VERSION 5.7 ;
  NOWIREEXTENSIONATPIN ON ;
  DIVIDERCHAR "/" ;
  BUSBITCHARS "[]" ;
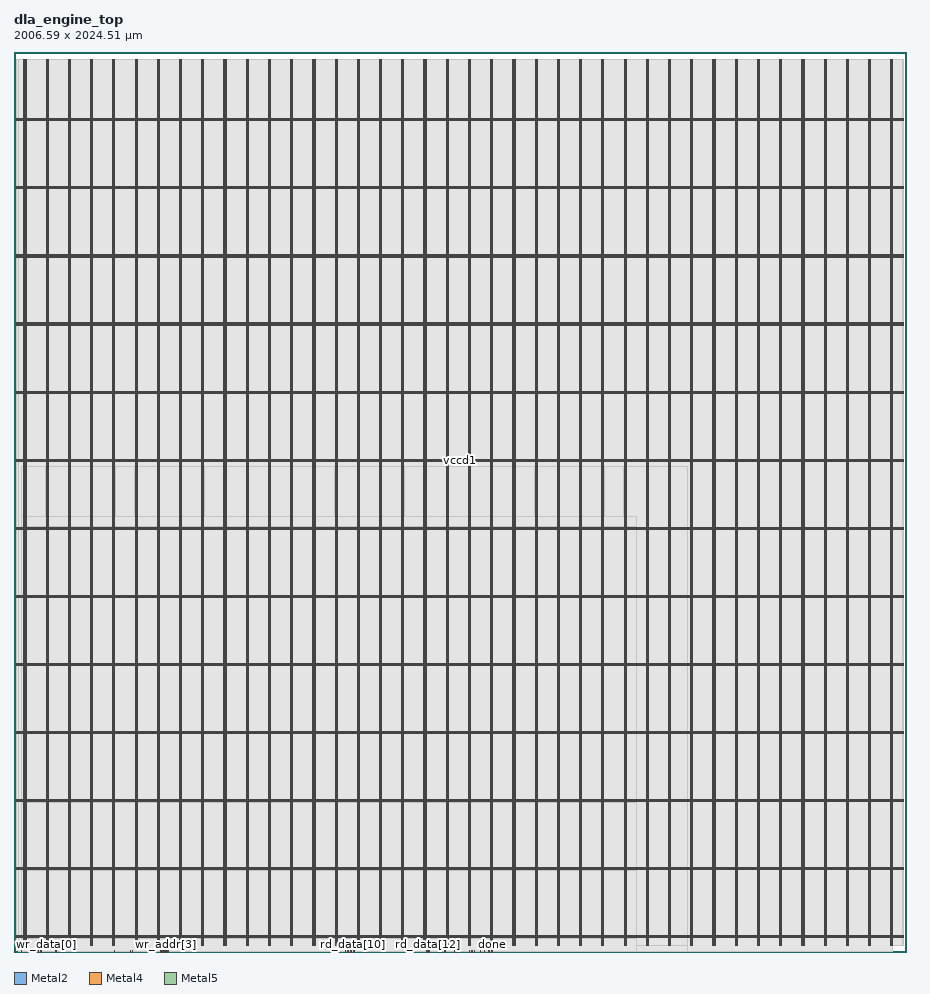
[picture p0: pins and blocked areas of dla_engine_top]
MACRO dla_engine_top
  CLASS BLOCK ;
  FOREIGN dla_engine_top ;
  ORIGIN 0.000 0.000 ;
  SIZE 2006.585 BY 2024.505 ;
  PIN busy
    DIRECTION OUTPUT ;
    USE SIGNAL ;
    ANTENNADIFFAREA 1.986000 ;
    PORT
      LAYER Metal2 ;
        RECT 1048.320 0.000 1048.880 4.000 ;
    END
  END busy
  PIN clk
    DIRECTION INPUT ;
    USE SIGNAL ;
    ANTENNAGATEAREA 4.738000 ;
    ANTENNADIFFAREA 0.820800 ;
    PORT
      LAYER Metal2 ;
        RECT 110.880 0.000 111.440 4.000 ;
    END
  END clk
  PIN done
    DIRECTION OUTPUT ;
    USE SIGNAL ;
    ANTENNADIFFAREA 1.986000 ;
    PORT
      LAYER Metal2 ;
        RECT 1075.200 0.000 1075.760 4.000 ;
    END
  END done
  PIN rd_addr[0]
    DIRECTION INPUT ;
    USE SIGNAL ;
    ANTENNAGATEAREA 0.396000 ;
    PORT
      LAYER Metal2 ;
        RECT 1028.160 0.000 1028.720 4.000 ;
    END
  END rd_addr[0]
  PIN rd_addr[1]
    DIRECTION INPUT ;
    USE SIGNAL ;
    ANTENNAGATEAREA 0.741000 ;
    PORT
      LAYER Metal2 ;
        RECT 1034.880 0.000 1035.440 4.000 ;
    END
  END rd_addr[1]
  PIN rd_addr[2]
    DIRECTION INPUT ;
    USE SIGNAL ;
    ANTENNAGATEAREA 0.396000 ;
    PORT
      LAYER Metal2 ;
        RECT 1024.800 0.000 1025.360 4.000 ;
    END
  END rd_addr[2]
  PIN rd_addr[3]
    DIRECTION INPUT ;
    USE SIGNAL ;
    ANTENNAGATEAREA 0.396000 ;
    PORT
      LAYER Metal2 ;
        RECT 1031.520 0.000 1032.080 4.000 ;
    END
  END rd_addr[3]
  PIN rd_data[0]
    DIRECTION OUTPUT ;
    USE SIGNAL ;
    ANTENNADIFFAREA 1.986000 ;
    PORT
      LAYER Metal2 ;
        RECT 725.760 0.000 726.320 4.000 ;
    END
  END rd_data[0]
  PIN rd_data[10]
    DIRECTION OUTPUT ;
    USE SIGNAL ;
    ANTENNADIFFAREA 1.986000 ;
    PORT
      LAYER Metal2 ;
        RECT 762.720 0.000 763.280 4.000 ;
    END
  END rd_data[10]
  PIN rd_data[11]
    DIRECTION OUTPUT ;
    USE SIGNAL ;
    ANTENNADIFFAREA 1.986000 ;
    PORT
      LAYER Metal2 ;
        RECT 789.600 0.000 790.160 4.000 ;
    END
  END rd_data[11]
  PIN rd_data[12]
    DIRECTION OUTPUT ;
    USE SIGNAL ;
    ANTENNADIFFAREA 1.986000 ;
    PORT
      LAYER Metal2 ;
        RECT 930.720 0.000 931.280 4.000 ;
    END
  END rd_data[12]
  PIN rd_data[13]
    DIRECTION OUTPUT ;
    USE SIGNAL ;
    ANTENNADIFFAREA 1.986000 ;
    PORT
      LAYER Metal2 ;
        RECT 957.600 0.000 958.160 4.000 ;
    END
  END rd_data[13]
  PIN rd_data[14]
    DIRECTION OUTPUT ;
    USE SIGNAL ;
    ANTENNADIFFAREA 1.986000 ;
    PORT
      LAYER Metal2 ;
        RECT 967.680 0.000 968.240 4.000 ;
    END
  END rd_data[14]
  PIN rd_data[15]
    DIRECTION OUTPUT ;
    USE SIGNAL ;
    ANTENNADIFFAREA 1.986000 ;
    PORT
      LAYER Metal2 ;
        RECT 997.920 0.000 998.480 4.000 ;
    END
  END rd_data[15]
  PIN rd_data[16]
    DIRECTION OUTPUT ;
    USE SIGNAL ;
    ANTENNADIFFAREA 1.986000 ;
    PORT
      LAYER Metal2 ;
        RECT 722.400 0.000 722.960 4.000 ;
    END
  END rd_data[16]
  PIN rd_data[17]
    DIRECTION OUTPUT ;
    USE SIGNAL ;
    ANTENNADIFFAREA 1.986000 ;
    PORT
      LAYER Metal2 ;
        RECT 752.640 0.000 753.200 4.000 ;
    END
  END rd_data[17]
  PIN rd_data[18]
    DIRECTION OUTPUT ;
    USE SIGNAL ;
    ANTENNADIFFAREA 1.986000 ;
    PORT
      LAYER Metal2 ;
        RECT 759.360 0.000 759.920 4.000 ;
    END
  END rd_data[18]
  PIN rd_data[19]
    DIRECTION OUTPUT ;
    USE SIGNAL ;
    ANTENNADIFFAREA 1.986000 ;
    PORT
      LAYER Metal2 ;
        RECT 792.960 0.000 793.520 4.000 ;
    END
  END rd_data[19]
  PIN rd_data[1]
    DIRECTION OUTPUT ;
    USE SIGNAL ;
    ANTENNADIFFAREA 1.986000 ;
    PORT
      LAYER Metal2 ;
        RECT 749.280 0.000 749.840 4.000 ;
    END
  END rd_data[1]
  PIN rd_data[20]
    DIRECTION OUTPUT ;
    USE SIGNAL ;
    ANTENNADIFFAREA 1.986000 ;
    PORT
      LAYER Metal2 ;
        RECT 934.080 0.000 934.640 4.000 ;
    END
  END rd_data[20]
  PIN rd_data[21]
    DIRECTION OUTPUT ;
    USE SIGNAL ;
    ANTENNADIFFAREA 1.986000 ;
    PORT
      LAYER Metal2 ;
        RECT 960.960 0.000 961.520 4.000 ;
    END
  END rd_data[21]
  PIN rd_data[22]
    DIRECTION OUTPUT ;
    USE SIGNAL ;
    ANTENNADIFFAREA 1.986000 ;
    PORT
      LAYER Metal2 ;
        RECT 971.040 0.000 971.600 4.000 ;
    END
  END rd_data[22]
  PIN rd_data[23]
    DIRECTION OUTPUT ;
    USE SIGNAL ;
    ANTENNADIFFAREA 1.986000 ;
    PORT
      LAYER Metal2 ;
        RECT 994.560 0.000 995.120 4.000 ;
    END
  END rd_data[23]
  PIN rd_data[2]
    DIRECTION OUTPUT ;
    USE SIGNAL ;
    ANTENNADIFFAREA 1.986000 ;
    PORT
      LAYER Metal2 ;
        RECT 756.000 0.000 756.560 4.000 ;
    END
  END rd_data[2]
  PIN rd_data[3]
    DIRECTION OUTPUT ;
    USE SIGNAL ;
    ANTENNADIFFAREA 1.986000 ;
    PORT
      LAYER Metal2 ;
        RECT 786.240 0.000 786.800 4.000 ;
    END
  END rd_data[3]
  PIN rd_data[4]
    DIRECTION OUTPUT ;
    USE SIGNAL ;
    ANTENNADIFFAREA 1.986000 ;
    PORT
      LAYER Metal2 ;
        RECT 927.360 0.000 927.920 4.000 ;
    END
  END rd_data[4]
  PIN rd_data[5]
    DIRECTION OUTPUT ;
    USE SIGNAL ;
    ANTENNADIFFAREA 1.986000 ;
    PORT
      LAYER Metal2 ;
        RECT 954.240 0.000 954.800 4.000 ;
    END
  END rd_data[5]
  PIN rd_data[6]
    DIRECTION OUTPUT ;
    USE SIGNAL ;
    ANTENNADIFFAREA 1.986000 ;
    PORT
      LAYER Metal2 ;
        RECT 964.320 0.000 964.880 4.000 ;
    END
  END rd_data[6]
  PIN rd_data[7]
    DIRECTION OUTPUT ;
    USE SIGNAL ;
    ANTENNADIFFAREA 1.986000 ;
    PORT
      LAYER Metal2 ;
        RECT 991.200 0.000 991.760 4.000 ;
    END
  END rd_data[7]
  PIN rd_data[8]
    DIRECTION OUTPUT ;
    USE SIGNAL ;
    ANTENNADIFFAREA 1.986000 ;
    PORT
      LAYER Metal2 ;
        RECT 719.040 0.000 719.600 4.000 ;
    END
  END rd_data[8]
  PIN rd_data[9]
    DIRECTION OUTPUT ;
    USE SIGNAL ;
    ANTENNADIFFAREA 1.986000 ;
    PORT
      LAYER Metal2 ;
        RECT 745.920 0.000 746.480 4.000 ;
    END
  END rd_data[9]
  PIN rd_en
    DIRECTION INPUT ;
    USE SIGNAL ;
    PORT
      LAYER Metal2 ;
        RECT 0.000 0.000 0.560 4.000 ;
    END
  END rd_en
  PIN rst_n
    DIRECTION INPUT ;
    USE SIGNAL ;
    ANTENNAGATEAREA 0.396000 ;
    PORT
      LAYER Metal2 ;
        RECT 766.080 0.000 766.640 4.000 ;
    END
  END rst_n
  PIN start
    DIRECTION INPUT ;
    USE SIGNAL ;
    ANTENNAGATEAREA 0.396000 ;
    PORT
      LAYER Metal2 ;
        RECT 1058.400 0.000 1058.960 4.000 ;
    END
  END start
  PIN vccd1
    DIRECTION INOUT ;
    USE POWER ;
    PORT
      LAYER Metal4 ;
        RECT 22.240 15.380 23.840 2007.340 ;
    END
    PORT
      LAYER Metal4 ;
        RECT 72.240 15.380 73.840 2007.340 ;
    END
    PORT
      LAYER Metal4 ;
        RECT 122.240 15.380 123.840 2007.340 ;
    END
    PORT
      LAYER Metal4 ;
        RECT 172.240 15.380 173.840 2007.340 ;
    END
    PORT
      LAYER Metal4 ;
        RECT 222.240 15.380 223.840 2007.340 ;
    END
    PORT
      LAYER Metal4 ;
        RECT 272.240 15.380 273.840 2007.340 ;
    END
    PORT
      LAYER Metal4 ;
        RECT 322.240 15.380 323.840 2007.340 ;
    END
    PORT
      LAYER Metal4 ;
        RECT 372.240 15.380 373.840 2007.340 ;
    END
    PORT
      LAYER Metal4 ;
        RECT 422.240 15.380 423.840 2007.340 ;
    END
    PORT
      LAYER Metal4 ;
        RECT 472.240 15.380 473.840 2007.340 ;
    END
    PORT
      LAYER Metal4 ;
        RECT 522.240 15.380 523.840 2007.340 ;
    END
    PORT
      LAYER Metal4 ;
        RECT 572.240 15.380 573.840 2007.340 ;
    END
    PORT
      LAYER Metal4 ;
        RECT 622.240 15.380 623.840 2007.340 ;
    END
    PORT
      LAYER Metal4 ;
        RECT 672.240 15.380 673.840 2007.340 ;
    END
    PORT
      LAYER Metal4 ;
        RECT 722.240 15.380 723.840 2007.340 ;
    END
    PORT
      LAYER Metal4 ;
        RECT 772.240 15.380 773.840 2007.340 ;
    END
    PORT
      LAYER Metal4 ;
        RECT 822.240 15.380 823.840 2007.340 ;
    END
    PORT
      LAYER Metal4 ;
        RECT 872.240 15.380 873.840 2007.340 ;
    END
    PORT
      LAYER Metal4 ;
        RECT 922.240 15.380 923.840 2007.340 ;
    END
    PORT
      LAYER Metal4 ;
        RECT 972.240 15.380 973.840 2007.340 ;
    END
    PORT
      LAYER Metal4 ;
        RECT 1022.240 15.380 1023.840 2007.340 ;
    END
    PORT
      LAYER Metal4 ;
        RECT 1072.240 15.380 1073.840 2007.340 ;
    END
    PORT
      LAYER Metal4 ;
        RECT 1122.240 15.380 1123.840 2007.340 ;
    END
    PORT
      LAYER Metal4 ;
        RECT 1172.240 15.380 1173.840 2007.340 ;
    END
    PORT
      LAYER Metal4 ;
        RECT 1222.240 15.380 1223.840 2007.340 ;
    END
    PORT
      LAYER Metal4 ;
        RECT 1272.240 15.380 1273.840 2007.340 ;
    END
    PORT
      LAYER Metal4 ;
        RECT 1322.240 15.380 1323.840 2007.340 ;
    END
    PORT
      LAYER Metal4 ;
        RECT 1372.240 15.380 1373.840 2007.340 ;
    END
    PORT
      LAYER Metal4 ;
        RECT 1422.240 15.380 1423.840 2007.340 ;
    END
    PORT
      LAYER Metal4 ;
        RECT 1472.240 15.380 1473.840 2007.340 ;
    END
    PORT
      LAYER Metal4 ;
        RECT 1522.240 15.380 1523.840 2007.340 ;
    END
    PORT
      LAYER Metal4 ;
        RECT 1572.240 15.380 1573.840 2007.340 ;
    END
    PORT
      LAYER Metal4 ;
        RECT 1622.240 15.380 1623.840 2007.340 ;
    END
    PORT
      LAYER Metal4 ;
        RECT 1672.240 15.380 1673.840 2007.340 ;
    END
    PORT
      LAYER Metal4 ;
        RECT 1722.240 15.380 1723.840 2007.340 ;
    END
    PORT
      LAYER Metal4 ;
        RECT 1772.240 15.380 1773.840 2007.340 ;
    END
    PORT
      LAYER Metal4 ;
        RECT 1822.240 15.380 1823.840 2007.340 ;
    END
    PORT
      LAYER Metal4 ;
        RECT 1872.240 15.380 1873.840 2007.340 ;
    END
    PORT
      LAYER Metal4 ;
        RECT 1922.240 15.380 1923.840 2007.340 ;
    END
    PORT
      LAYER Metal4 ;
        RECT 1972.240 15.380 1973.840 2007.340 ;
    END
    PORT
      LAYER Metal5 ;
        RECT 6.420 31.530 2000.060 33.130 ;
    END
    PORT
      LAYER Metal5 ;
        RECT 6.420 184.710 2000.060 186.310 ;
    END
    PORT
      LAYER Metal5 ;
        RECT 6.420 337.890 2000.060 339.490 ;
    END
    PORT
      LAYER Metal5 ;
        RECT 6.420 491.070 2000.060 492.670 ;
    END
    PORT
      LAYER Metal5 ;
        RECT 6.420 644.250 2000.060 645.850 ;
    END
    PORT
      LAYER Metal5 ;
        RECT 6.420 797.430 2000.060 799.030 ;
    END
    PORT
      LAYER Metal5 ;
        RECT 6.420 950.610 2000.060 952.210 ;
    END
    PORT
      LAYER Metal5 ;
        RECT 6.420 1103.790 2000.060 1105.390 ;
    END
    PORT
      LAYER Metal5 ;
        RECT 6.420 1256.970 2000.060 1258.570 ;
    END
    PORT
      LAYER Metal5 ;
        RECT 6.420 1410.150 2000.060 1411.750 ;
    END
    PORT
      LAYER Metal5 ;
        RECT 6.420 1563.330 2000.060 1564.930 ;
    END
    PORT
      LAYER Metal5 ;
        RECT 6.420 1716.510 2000.060 1718.110 ;
    END
    PORT
      LAYER Metal5 ;
        RECT 6.420 1869.690 2000.060 1871.290 ;
    END
  END vccd1
  PIN vssd1
    DIRECTION INOUT ;
    USE GROUND ;
    PORT
      LAYER Metal4 ;
        RECT 25.540 15.380 27.140 2007.340 ;
    END
    PORT
      LAYER Metal4 ;
        RECT 75.540 15.380 77.140 2007.340 ;
    END
    PORT
      LAYER Metal4 ;
        RECT 125.540 15.380 127.140 2007.340 ;
    END
    PORT
      LAYER Metal4 ;
        RECT 175.540 15.380 177.140 2007.340 ;
    END
    PORT
      LAYER Metal4 ;
        RECT 225.540 15.380 227.140 2007.340 ;
    END
    PORT
      LAYER Metal4 ;
        RECT 275.540 15.380 277.140 2007.340 ;
    END
    PORT
      LAYER Metal4 ;
        RECT 325.540 15.380 327.140 2007.340 ;
    END
    PORT
      LAYER Metal4 ;
        RECT 375.540 15.380 377.140 2007.340 ;
    END
    PORT
      LAYER Metal4 ;
        RECT 425.540 15.380 427.140 2007.340 ;
    END
    PORT
      LAYER Metal4 ;
        RECT 475.540 15.380 477.140 2007.340 ;
    END
    PORT
      LAYER Metal4 ;
        RECT 525.540 15.380 527.140 2007.340 ;
    END
    PORT
      LAYER Metal4 ;
        RECT 575.540 15.380 577.140 2007.340 ;
    END
    PORT
      LAYER Metal4 ;
        RECT 625.540 15.380 627.140 2007.340 ;
    END
    PORT
      LAYER Metal4 ;
        RECT 675.540 15.380 677.140 2007.340 ;
    END
    PORT
      LAYER Metal4 ;
        RECT 725.540 15.380 727.140 2007.340 ;
    END
    PORT
      LAYER Metal4 ;
        RECT 775.540 15.380 777.140 2007.340 ;
    END
    PORT
      LAYER Metal4 ;
        RECT 825.540 15.380 827.140 2007.340 ;
    END
    PORT
      LAYER Metal4 ;
        RECT 875.540 15.380 877.140 2007.340 ;
    END
    PORT
      LAYER Metal4 ;
        RECT 925.540 15.380 927.140 2007.340 ;
    END
    PORT
      LAYER Metal4 ;
        RECT 975.540 15.380 977.140 2007.340 ;
    END
    PORT
      LAYER Metal4 ;
        RECT 1025.540 15.380 1027.140 2007.340 ;
    END
    PORT
      LAYER Metal4 ;
        RECT 1075.540 15.380 1077.140 2007.340 ;
    END
    PORT
      LAYER Metal4 ;
        RECT 1125.540 15.380 1127.140 2007.340 ;
    END
    PORT
      LAYER Metal4 ;
        RECT 1175.540 15.380 1177.140 2007.340 ;
    END
    PORT
      LAYER Metal4 ;
        RECT 1225.540 15.380 1227.140 2007.340 ;
    END
    PORT
      LAYER Metal4 ;
        RECT 1275.540 15.380 1277.140 2007.340 ;
    END
    PORT
      LAYER Metal4 ;
        RECT 1325.540 15.380 1327.140 2007.340 ;
    END
    PORT
      LAYER Metal4 ;
        RECT 1375.540 15.380 1377.140 2007.340 ;
    END
    PORT
      LAYER Metal4 ;
        RECT 1425.540 15.380 1427.140 2007.340 ;
    END
    PORT
      LAYER Metal4 ;
        RECT 1475.540 15.380 1477.140 2007.340 ;
    END
    PORT
      LAYER Metal4 ;
        RECT 1525.540 15.380 1527.140 2007.340 ;
    END
    PORT
      LAYER Metal4 ;
        RECT 1575.540 15.380 1577.140 2007.340 ;
    END
    PORT
      LAYER Metal4 ;
        RECT 1625.540 15.380 1627.140 2007.340 ;
    END
    PORT
      LAYER Metal4 ;
        RECT 1675.540 15.380 1677.140 2007.340 ;
    END
    PORT
      LAYER Metal4 ;
        RECT 1725.540 15.380 1727.140 2007.340 ;
    END
    PORT
      LAYER Metal4 ;
        RECT 1775.540 15.380 1777.140 2007.340 ;
    END
    PORT
      LAYER Metal4 ;
        RECT 1825.540 15.380 1827.140 2007.340 ;
    END
    PORT
      LAYER Metal4 ;
        RECT 1875.540 15.380 1877.140 2007.340 ;
    END
    PORT
      LAYER Metal4 ;
        RECT 1925.540 15.380 1927.140 2007.340 ;
    END
    PORT
      LAYER Metal4 ;
        RECT 1975.540 15.380 1977.140 2007.340 ;
    END
    PORT
      LAYER Metal5 ;
        RECT 6.420 34.830 2000.060 36.430 ;
    END
    PORT
      LAYER Metal5 ;
        RECT 6.420 188.010 2000.060 189.610 ;
    END
    PORT
      LAYER Metal5 ;
        RECT 6.420 341.190 2000.060 342.790 ;
    END
    PORT
      LAYER Metal5 ;
        RECT 6.420 494.370 2000.060 495.970 ;
    END
    PORT
      LAYER Metal5 ;
        RECT 6.420 647.550 2000.060 649.150 ;
    END
    PORT
      LAYER Metal5 ;
        RECT 6.420 800.730 2000.060 802.330 ;
    END
    PORT
      LAYER Metal5 ;
        RECT 6.420 953.910 2000.060 955.510 ;
    END
    PORT
      LAYER Metal5 ;
        RECT 6.420 1107.090 2000.060 1108.690 ;
    END
    PORT
      LAYER Metal5 ;
        RECT 6.420 1260.270 2000.060 1261.870 ;
    END
    PORT
      LAYER Metal5 ;
        RECT 6.420 1413.450 2000.060 1415.050 ;
    END
    PORT
      LAYER Metal5 ;
        RECT 6.420 1566.630 2000.060 1568.230 ;
    END
    PORT
      LAYER Metal5 ;
        RECT 6.420 1719.810 2000.060 1721.410 ;
    END
    PORT
      LAYER Metal5 ;
        RECT 6.420 1872.990 2000.060 1874.590 ;
    END
  END vssd1
  PIN wb_done
    DIRECTION OUTPUT ;
    USE SIGNAL ;
    ANTENNADIFFAREA 1.986000 ;
    PORT
      LAYER Metal2 ;
        RECT 1068.480 0.000 1069.040 4.000 ;
    END
  END wb_done
  PIN wr_addr[0]
    DIRECTION INPUT ;
    USE SIGNAL ;
    ANTENNAGATEAREA 0.396000 ;
    PORT
      LAYER Metal2 ;
        RECT 329.280 0.000 329.840 4.000 ;
    END
  END wr_addr[0]
  PIN wr_addr[1]
    DIRECTION INPUT ;
    USE SIGNAL ;
    ANTENNAGATEAREA 0.396000 ;
    ANTENNADIFFAREA 0.820800 ;
    PORT
      LAYER Metal2 ;
        RECT 332.640 0.000 333.200 4.000 ;
    END
  END wr_addr[1]
  PIN wr_addr[2]
    DIRECTION INPUT ;
    USE SIGNAL ;
    ANTENNAGATEAREA 0.396000 ;
    ANTENNADIFFAREA 0.410400 ;
    PORT
      LAYER Metal2 ;
        RECT 346.080 0.000 346.640 4.000 ;
    END
  END wr_addr[2]
  PIN wr_addr[3]
    DIRECTION INPUT ;
    USE SIGNAL ;
    ANTENNAGATEAREA 0.396000 ;
    ANTENNADIFFAREA 0.410400 ;
    PORT
      LAYER Metal2 ;
        RECT 342.720 0.000 343.280 4.000 ;
    END
  END wr_addr[3]
  PIN wr_data[0]
    DIRECTION INPUT ;
    USE SIGNAL ;
    ANTENNAGATEAREA 0.396000 ;
    ANTENNADIFFAREA 0.410400 ;
    PORT
      LAYER Metal2 ;
        RECT 16.800 0.000 17.360 4.000 ;
    END
  END wr_data[0]
  PIN wr_data[1]
    DIRECTION INPUT ;
    USE SIGNAL ;
    ANTENNAGATEAREA 0.396000 ;
    ANTENNADIFFAREA 0.410400 ;
    PORT
      LAYER Metal2 ;
        RECT 53.760 0.000 54.320 4.000 ;
    END
  END wr_data[1]
  PIN wr_data[2]
    DIRECTION INPUT ;
    USE SIGNAL ;
    ANTENNAGATEAREA 0.396000 ;
    ANTENNADIFFAREA 0.410400 ;
    PORT
      LAYER Metal2 ;
        RECT 60.480 0.000 61.040 4.000 ;
    END
  END wr_data[2]
  PIN wr_data[3]
    DIRECTION INPUT ;
    USE SIGNAL ;
    ANTENNAGATEAREA 0.396000 ;
    ANTENNADIFFAREA 0.410400 ;
    PORT
      LAYER Metal2 ;
        RECT 94.080 0.000 94.640 4.000 ;
    END
  END wr_data[3]
  PIN wr_data[4]
    DIRECTION INPUT ;
    USE SIGNAL ;
    ANTENNAGATEAREA 0.396000 ;
    ANTENNADIFFAREA 0.410400 ;
    PORT
      LAYER Metal2 ;
        RECT 225.120 0.000 225.680 4.000 ;
    END
  END wr_data[4]
  PIN wr_data[5]
    DIRECTION INPUT ;
    USE SIGNAL ;
    ANTENNAGATEAREA 0.396000 ;
    ANTENNADIFFAREA 0.820800 ;
    PORT
      LAYER Metal2 ;
        RECT 262.080 0.000 262.640 4.000 ;
    END
  END wr_data[5]
  PIN wr_data[6]
    DIRECTION INPUT ;
    USE SIGNAL ;
    ANTENNAGATEAREA 0.396000 ;
    ANTENNADIFFAREA 1.231200 ;
    PORT
      LAYER Metal2 ;
        RECT 265.440 0.000 266.000 4.000 ;
    END
  END wr_data[6]
  PIN wr_data[7]
    DIRECTION INPUT ;
    USE SIGNAL ;
    ANTENNAGATEAREA 0.396000 ;
    ANTENNADIFFAREA 0.410400 ;
    PORT
      LAYER Metal2 ;
        RECT 302.400 0.000 302.960 4.000 ;
    END
  END wr_data[7]
  PIN wr_en
    DIRECTION INPUT ;
    USE SIGNAL ;
    ANTENNAGATEAREA 0.396000 ;
    ANTENNADIFFAREA 0.410400 ;
    PORT
      LAYER Metal2 ;
        RECT 339.360 0.000 339.920 4.000 ;
    END
  END wr_en
  PIN wr_sel
    DIRECTION INPUT ;
    USE SIGNAL ;
    ANTENNAGATEAREA 1.183000 ;
    PORT
      LAYER Metal2 ;
        RECT 336.000 0.000 336.560 4.000 ;
    END
  END wr_sel
  OBS
      LAYER Nwell ;
        RECT 6.290 15.250 2000.190 2007.470 ;
      LAYER Metal1 ;
        RECT 6.720 15.380 1999.760 2007.340 ;
      LAYER Metal2 ;
        RECT 10.985 4.300 1977.000 2007.230 ;
        RECT 10.985 0.650 16.500 4.300 ;
        RECT 17.660 0.650 53.460 4.300 ;
        RECT 54.620 0.650 60.180 4.300 ;
        RECT 61.340 0.650 93.780 4.300 ;
        RECT 94.940 0.650 110.580 4.300 ;
        RECT 111.740 0.650 224.820 4.300 ;
        RECT 225.980 0.650 261.780 4.300 ;
        RECT 262.940 0.650 265.140 4.300 ;
        RECT 266.300 0.650 302.100 4.300 ;
        RECT 303.260 0.650 328.980 4.300 ;
        RECT 330.140 0.650 332.340 4.300 ;
        RECT 333.500 0.650 335.700 4.300 ;
        RECT 336.860 0.650 339.060 4.300 ;
        RECT 340.220 0.650 342.420 4.300 ;
        RECT 343.580 0.650 345.780 4.300 ;
        RECT 346.940 0.650 718.740 4.300 ;
        RECT 719.900 0.650 722.100 4.300 ;
        RECT 723.260 0.650 725.460 4.300 ;
        RECT 726.620 0.650 745.620 4.300 ;
        RECT 746.780 0.650 748.980 4.300 ;
        RECT 750.140 0.650 752.340 4.300 ;
        RECT 753.500 0.650 755.700 4.300 ;
        RECT 756.860 0.650 759.060 4.300 ;
        RECT 760.220 0.650 762.420 4.300 ;
        RECT 763.580 0.650 765.780 4.300 ;
        RECT 766.940 0.650 785.940 4.300 ;
        RECT 787.100 0.650 789.300 4.300 ;
        RECT 790.460 0.650 792.660 4.300 ;
        RECT 793.820 0.650 927.060 4.300 ;
        RECT 928.220 0.650 930.420 4.300 ;
        RECT 931.580 0.650 933.780 4.300 ;
        RECT 934.940 0.650 953.940 4.300 ;
        RECT 955.100 0.650 957.300 4.300 ;
        RECT 958.460 0.650 960.660 4.300 ;
        RECT 961.820 0.650 964.020 4.300 ;
        RECT 965.180 0.650 967.380 4.300 ;
        RECT 968.540 0.650 970.740 4.300 ;
        RECT 971.900 0.650 990.900 4.300 ;
        RECT 992.060 0.650 994.260 4.300 ;
        RECT 995.420 0.650 997.620 4.300 ;
        RECT 998.780 0.650 1024.500 4.300 ;
        RECT 1025.660 0.650 1027.860 4.300 ;
        RECT 1029.020 0.650 1031.220 4.300 ;
        RECT 1032.380 0.650 1034.580 4.300 ;
        RECT 1035.740 0.650 1048.020 4.300 ;
        RECT 1049.180 0.650 1058.100 4.300 ;
        RECT 1059.260 0.650 1068.180 4.300 ;
        RECT 1069.340 0.650 1074.900 4.300 ;
        RECT 1076.060 0.650 1977.000 4.300 ;
      LAYER Metal3 ;
        RECT 10.000 0.700 1977.050 2007.180 ;
      LAYER Metal4 ;
        RECT 16.940 15.080 21.940 1092.470 ;
        RECT 24.140 15.080 25.240 1092.470 ;
        RECT 27.440 15.080 71.940 1092.470 ;
        RECT 74.140 15.080 75.240 1092.470 ;
        RECT 77.440 15.080 121.940 1092.470 ;
        RECT 124.140 15.080 125.240 1092.470 ;
        RECT 127.440 15.080 171.940 1092.470 ;
        RECT 174.140 15.080 175.240 1092.470 ;
        RECT 177.440 15.080 221.940 1092.470 ;
        RECT 224.140 15.080 225.240 1092.470 ;
        RECT 227.440 15.080 271.940 1092.470 ;
        RECT 274.140 15.080 275.240 1092.470 ;
        RECT 277.440 15.080 321.940 1092.470 ;
        RECT 324.140 15.080 325.240 1092.470 ;
        RECT 327.440 15.080 371.940 1092.470 ;
        RECT 374.140 15.080 375.240 1092.470 ;
        RECT 377.440 15.080 421.940 1092.470 ;
        RECT 424.140 15.080 425.240 1092.470 ;
        RECT 427.440 15.080 471.940 1092.470 ;
        RECT 474.140 15.080 475.240 1092.470 ;
        RECT 477.440 15.080 521.940 1092.470 ;
        RECT 524.140 15.080 525.240 1092.470 ;
        RECT 527.440 15.080 571.940 1092.470 ;
        RECT 574.140 15.080 575.240 1092.470 ;
        RECT 577.440 15.080 621.940 1092.470 ;
        RECT 624.140 15.080 625.240 1092.470 ;
        RECT 627.440 15.080 671.940 1092.470 ;
        RECT 674.140 15.080 675.240 1092.470 ;
        RECT 677.440 15.080 721.940 1092.470 ;
        RECT 724.140 15.080 725.240 1092.470 ;
        RECT 727.440 15.080 771.940 1092.470 ;
        RECT 774.140 15.080 775.240 1092.470 ;
        RECT 777.440 15.080 821.940 1092.470 ;
        RECT 824.140 15.080 825.240 1092.470 ;
        RECT 827.440 15.080 871.940 1092.470 ;
        RECT 874.140 15.080 875.240 1092.470 ;
        RECT 877.440 15.080 921.940 1092.470 ;
        RECT 924.140 15.080 925.240 1092.470 ;
        RECT 927.440 15.080 971.940 1092.470 ;
        RECT 974.140 15.080 975.240 1092.470 ;
        RECT 977.440 15.080 1021.940 1092.470 ;
        RECT 1024.140 15.080 1025.240 1092.470 ;
        RECT 1027.440 15.080 1071.940 1092.470 ;
        RECT 1074.140 15.080 1075.240 1092.470 ;
        RECT 1077.440 15.080 1121.940 1092.470 ;
        RECT 1124.140 15.080 1125.240 1092.470 ;
        RECT 1127.440 15.080 1171.940 1092.470 ;
        RECT 1174.140 15.080 1175.240 1092.470 ;
        RECT 1177.440 15.080 1221.940 1092.470 ;
        RECT 1224.140 15.080 1225.240 1092.470 ;
        RECT 1227.440 15.080 1271.940 1092.470 ;
        RECT 1274.140 15.080 1275.240 1092.470 ;
        RECT 1277.440 15.080 1321.940 1092.470 ;
        RECT 1324.140 15.080 1325.240 1092.470 ;
        RECT 1327.440 15.080 1371.940 1092.470 ;
        RECT 1374.140 15.080 1375.240 1092.470 ;
        RECT 1377.440 15.080 1421.940 1092.470 ;
        RECT 1424.140 15.080 1425.240 1092.470 ;
        RECT 1427.440 15.080 1471.940 1092.470 ;
        RECT 1474.140 15.080 1475.240 1092.470 ;
        RECT 1477.440 15.080 1515.780 1092.470 ;
        RECT 16.940 0.260 1515.780 15.080 ;
      LAYER Metal5 ;
        RECT 16.860 956.110 1401.060 978.970 ;
        RECT 16.860 952.810 1401.060 953.310 ;
        RECT 16.860 802.930 1401.060 950.010 ;
        RECT 16.860 799.630 1401.060 800.130 ;
        RECT 16.860 649.750 1401.060 796.830 ;
        RECT 16.860 646.450 1401.060 646.950 ;
        RECT 16.860 496.570 1401.060 643.650 ;
        RECT 16.860 493.270 1401.060 493.770 ;
        RECT 16.860 343.390 1401.060 490.470 ;
        RECT 16.860 340.090 1401.060 340.590 ;
        RECT 16.860 190.210 1401.060 337.290 ;
        RECT 16.860 186.910 1401.060 187.410 ;
        RECT 16.860 37.030 1401.060 184.110 ;
        RECT 16.860 33.730 1401.060 34.230 ;
        RECT 16.860 0.230 1401.060 30.930 ;
  END
END dla_engine_top
END LIBRARY

